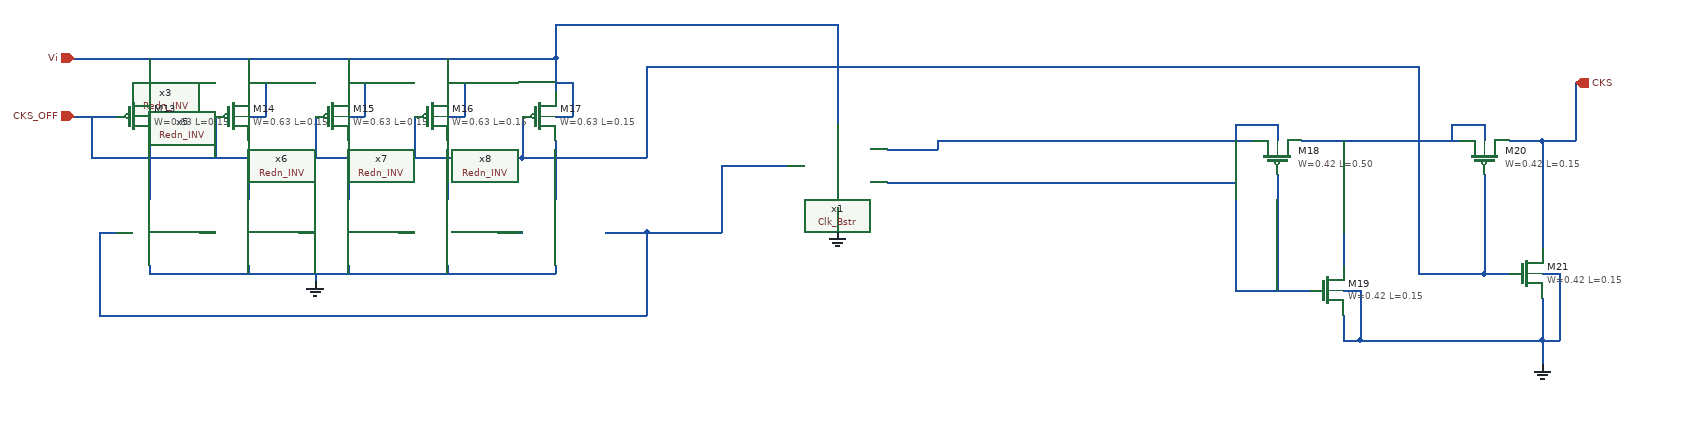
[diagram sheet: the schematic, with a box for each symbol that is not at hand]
v {xschem version=3.0.0 file_version=1.2 }
G {}
K {}
V {}
S {}
E {}
N 690 -790 690 -650 {
lab=#net1}
N 820 -830 910 -830 {
lab=#net2}
N 940 -790 940 -670 {
lab=CKS_OFF}
N 940 -670 970 -670 {
lab=CKS_OFF}
N 770 -650 790 -650 {
lab=GND}
N 790 -650 790 -600 {
lab=GND}
N 1010 -670 1030 -670 {
lab=GND}
N 1030 -670 1030 -610 {
lab=GND}
N 1010 -830 1010 -700 {
lab=CKS}
N 870 -670 940 -670 {
lab=CKS_OFF}
N 940 -850 940 -830 {
lab=#net2}
N 900 -850 940 -850 {
lab=#net2}
N 900 -850 900 -830 {
lab=#net2}
N 640 -650 730 -650 {
lab=#net1}
N 860 -670 870 -670 {
lab=CKS_OFF}
N 640 -850 640 -830 {
lab=#net3}
N 640 -850 690 -850 {
lab=#net3}
N 690 -850 690 -830 {
lab=#net3}
N 1050 -900 1050 -830 {
lab=CKS}
N 790 -600 790 -590 {
lab=GND}
N 770 -590 790 -590 {
lab=GND}
N 780 -830 820 -830 {
lab=#net2}
N 770 -730 770 -680 {
lab=#net2}
N 720 -830 780 -830 {
lab=#net2}
N 770 -830 770 -730 {
lab=#net2}
N 1030 -610 1030 -590 {
lab=GND}
N 1010 -640 1010 -590 {
lab=GND}
N 770 -620 770 -590 {
lab=GND}
N 970 -830 1010 -830 {
lab=CKS}
N 1010 -830 1050 -830 {
lab=CKS}
N 280 -830 660 -830 {
lab=#net3}
N -610 -720 -590 -720 {
lab=#net4}
N -490 -720 -470 -720 {
lab=#net5}
N -370 -720 -350 -720 {
lab=#net6}
N -250 -720 -220 -720 {
lab=#net7}
N -670 -680 -670 -670 {
lab=GND}
N -670 -670 -180 -670 {
lab=GND}
N -180 -680 -180 -670 {
lab=GND}
N -310 -680 -310 -670 {
lab=GND}
N -430 -680 -430 -670 {
lab=GND}
N -550 -680 -550 -670 {
lab=GND}
N -730 -720 -710 -720 {
lab=#net8}
N -730 -720 -730 -620 {
lab=#net8}
N -120 -720 -70 -720 {
lab=#net8}
N -120 -720 -70 -720 {
lab=#net8}
N -180 -780 -180 -760 {
lab=#net9}
N -310 -780 -310 -760 {
lab=#net10}
N -430 -780 -430 -760 {
lab=#net11}
N -550 -780 -550 -760 {
lab=#net12}
N -670 -780 -670 -760 {
lab=#net13}
N -470 -670 -470 -660 {
lab=GND}
N -70 -720 -40 -720 {
lab=#net8}
N -70 -720 -70 -620 {
lab=#net8}
N -730 -620 -70 -620 {
lab=#net8}
N -670 -830 -670 -780 {
lab=#net13}
N -550 -830 -550 -780 {
lab=#net12}
N -430 -830 -430 -780 {
lab=#net11}
N -310 -830 -310 -780 {
lab=#net10}
N -180 -830 -180 -780 {
lab=#net9}
N -760 -860 -710 -860 {
lab=CKS_OFF}
N -740 -860 -740 -810 {
lab=CKS_OFF}
N -740 -810 -220 -810 {
lab=CKS_OFF}
N -220 -860 -220 -810 {
lab=CKS_OFF}
N -350 -860 -350 -810 {
lab=CKS_OFF}
N -470 -860 -470 -810 {
lab=CKS_OFF}
N -590 -860 -590 -810 {
lab=CKS_OFF}
N -760 -930 -190 -930 {
lab=Vi}
N -190 -930 -180 -930 {
lab=Vi}
N -180 -930 -180 -890 {
lab=Vi}
N -310 -930 -310 -890 {
lab=Vi}
N -430 -930 -430 -890 {
lab=Vi}
N -550 -930 -550 -890 {
lab=Vi}
N -670 -930 -670 -890 {
lab=Vi}
N -670 -860 -650 -860 {
lab=Vi}
N -650 -900 -650 -860 {
lab=Vi}
N -670 -900 -650 -900 {
lab=Vi}
N -550 -860 -530 -860 {
lab=Vi}
N -530 -900 -530 -860 {
lab=Vi}
N -550 -900 -530 -900 {
lab=Vi}
N -430 -860 -410 -860 {
lab=Vi}
N -410 -900 -410 -860 {
lab=Vi}
N -430 -900 -410 -900 {
lab=Vi}
N -310 -860 -290 -860 {
lab=Vi}
N -290 -900 -290 -860 {
lab=Vi}
N -310 -900 -290 -900 {
lab=Vi}
N -180 -860 -160 -860 {
lab=Vi}
N -160 -900 -160 -860 {
lab=Vi}
N -180 -900 -160 -900 {
lab=Vi}
N -220 -810 -70 -810 {
lab=CKS_OFF}
N -70 -860 -70 -810 {
lab=CKS_OFF}
N 220 -780 640 -780 {
lab=#net1}
N 640 -780 640 -650 {
lab=#net1}
N 220 -820 280 -820 {
lab=#net3}
N 280 -830 280 -820 {
lab=#net3}
N -40 -720 20 -720 {
lab=#net8}
N 20 -800 20 -720 {
lab=#net8}
N 20 -800 100 -800 {
lab=#net8}
N -70 -910 -70 -860 {
lab=CKS_OFF}
N -70 -920 -70 -910 {
lab=CKS_OFF}
N -70 -920 860 -920 {
lab=CKS_OFF}
N 860 -920 860 -670 {
lab=CKS_OFF}
N 790 -590 1010 -590 {
lab=GND}
N 1010 -590 1010 -560 {
lab=GND}
N 1010 -590 1030 -590 {
lab=GND}
N -180 -970 -180 -930 {
lab=Vi}
N -180 -970 160 -970 {
lab=Vi}
N 160 -970 160 -850 {
lab=Vi}
N 160 -750 160 -720 {
lab=#net14}
C {sky130_fd_pr/pfet_01v8.sym} 690 -810 3 0 {name=M18
L=0.50
W=0.42
nf=1
mult=1
ad="'int((nf+1)/2) * W/nf * 0.29'" 
pd="'2*int((nf+1)/2) * (W/nf + 0.29)'"
as="'int((nf+2)/2) * W/nf * 0.29'" 
ps="'2*int((nf+2)/2) * (W/nf + 0.29)'"
nrd="'0.29 / W'" nrs="'0.29 / W'"
sa=0 sb=0 sd=0
model=pfet_01v8
spiceprefix=X
}
C {sky130_fd_pr/nfet_01v8.sym} 750 -650 0 0 {name=M19
L=0.15
W=0.42
nf=1 
mult=1
ad="'int((nf+1)/2) * W/nf * 0.29'" 
pd="'2*int((nf+1)/2) * (W/nf + 0.29)'"
as="'int((nf+2)/2) * W/nf * 0.29'" 
ps="'2*int((nf+2)/2) * (W/nf + 0.29)'"
nrd="'0.29 / W'" nrs="'0.29 / W'"
sa=0 sb=0 sd=0
model=nfet_01v8
spiceprefix=X
}
C {sky130_fd_pr/nfet_01v8.sym} 990 -670 0 0 {name=M21
L=0.15
W=0.42
nf=1 
mult=1
ad="'int((nf+1)/2) * W/nf * 0.29'" 
pd="'2*int((nf+1)/2) * (W/nf + 0.29)'"
as="'int((nf+2)/2) * W/nf * 0.29'" 
ps="'2*int((nf+2)/2) * (W/nf + 0.29)'"
nrd="'0.29 / W'" nrs="'0.29 / W'"
sa=0 sb=0 sd=0
model=nfet_01v8
spiceprefix=X
}
C {sky130_fd_pr/pfet_01v8.sym} 940 -810 3 0 {name=M20
L=0.15
W=0.42
nf=1
mult=1
ad="'int((nf+1)/2) * W/nf * 0.29'" 
pd="'2*int((nf+1)/2) * (W/nf + 0.29)'"
as="'int((nf+2)/2) * W/nf * 0.29'" 
ps="'2*int((nf+2)/2) * (W/nf + 0.29)'"
nrd="'0.29 / W'" nrs="'0.29 / W'"
sa=0 sb=0 sd=0
model=pfet_01v8
spiceprefix=X
}
C {devices/opin.sym} 1050 -900 3 0 {name=p4 lab=CKS}
C {devices/gnd.sym} -470 -660 0 0 {name=l8 lab=GND}
C {Pico_project/Rdn_INV/Redn_INV.sym} -750 -680 0 0 {name=x3}
C {Pico_project/Rdn_INV/Redn_INV.sym} -630 -680 0 0 {name=x5}
C {Pico_project/Rdn_INV/Redn_INV.sym} -510 -680 0 0 {name=x6}
C {Pico_project/Rdn_INV/Redn_INV.sym} -390 -680 0 0 {name=x7}
C {Pico_project/Rdn_INV/Redn_INV.sym} -260 -680 0 0 {name=x8}
C {sky130_fd_pr/pfet_01v8.sym} -690 -860 0 0 {name=M13
L=0.15
W=0.63
nf=1
mult=1
ad="'int((nf+1)/2) * W/nf * 0.29'" 
pd="'2*int((nf+1)/2) * (W/nf + 0.29)'"
as="'int((nf+2)/2) * W/nf * 0.29'" 
ps="'2*int((nf+2)/2) * (W/nf + 0.29)'"
nrd="'0.29 / W'" nrs="'0.29 / W'"
sa=0 sb=0 sd=0
model=pfet_01v8
spiceprefix=X
}
C {sky130_fd_pr/pfet_01v8.sym} -570 -860 0 0 {name=M14
L=0.15
W=0.63
nf=1
mult=1
ad="'int((nf+1)/2) * W/nf * 0.29'" 
pd="'2*int((nf+1)/2) * (W/nf + 0.29)'"
as="'int((nf+2)/2) * W/nf * 0.29'" 
ps="'2*int((nf+2)/2) * (W/nf + 0.29)'"
nrd="'0.29 / W'" nrs="'0.29 / W'"
sa=0 sb=0 sd=0
model=pfet_01v8
spiceprefix=X
}
C {sky130_fd_pr/pfet_01v8.sym} -450 -860 0 0 {name=M15
L=0.15
W=0.63
nf=1
mult=1
ad="'int((nf+1)/2) * W/nf * 0.29'" 
pd="'2*int((nf+1)/2) * (W/nf + 0.29)'"
as="'int((nf+2)/2) * W/nf * 0.29'" 
ps="'2*int((nf+2)/2) * (W/nf + 0.29)'"
nrd="'0.29 / W'" nrs="'0.29 / W'"
sa=0 sb=0 sd=0
model=pfet_01v8
spiceprefix=X
}
C {sky130_fd_pr/pfet_01v8.sym} -330 -860 0 0 {name=M16
L=0.15
W=0.63
nf=1
mult=1
ad="'int((nf+1)/2) * W/nf * 0.29'" 
pd="'2*int((nf+1)/2) * (W/nf + 0.29)'"
as="'int((nf+2)/2) * W/nf * 0.29'" 
ps="'2*int((nf+2)/2) * (W/nf + 0.29)'"
nrd="'0.29 / W'" nrs="'0.29 / W'"
sa=0 sb=0 sd=0
model=pfet_01v8
spiceprefix=X
}
C {sky130_fd_pr/pfet_01v8.sym} -200 -860 0 0 {name=M17
L=0.15
W=0.63
nf=1
mult=1
ad="'int((nf+1)/2) * W/nf * 0.29'" 
pd="'2*int((nf+1)/2) * (W/nf + 0.29)'"
as="'int((nf+2)/2) * W/nf * 0.29'" 
ps="'2*int((nf+2)/2) * (W/nf + 0.29)'"
nrd="'0.29 / W'" nrs="'0.29 / W'"
sa=0 sb=0 sd=0
model=pfet_01v8
spiceprefix=X
}
C {devices/ipin.sym} -760 -860 0 0 {name=p5 lab=CKS_OFF}
C {devices/ipin.sym} -760 -930 0 0 {name=p6 lab=Vi}
C {Clk_Bstr.sym} 90 -770 0 0 {name=x1}
C {devices/gnd.sym} 1010 -560 0 0 {name=l1 lab=GND}
C {devices/gnd.sym} 160 -720 0 0 {name=l2 lab=GND}
